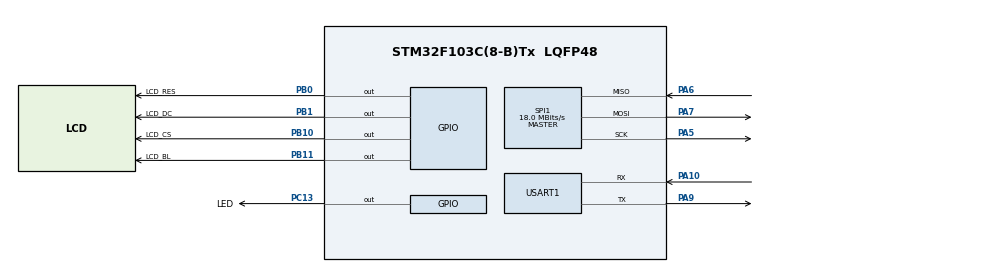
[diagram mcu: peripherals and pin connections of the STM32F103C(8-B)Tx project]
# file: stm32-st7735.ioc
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Mcu.Family=STM32F1
Mcu.Name=STM32F103C(8-B)Tx
Mcu.Package=LQFP48
NVIC.PriorityGroup=NVIC_PRIORITYGROUP_4
PA10.Mode=Asynchronous
PA10.Signal=USART1_RX
PA13.Mode=Serial_Wire
PA13.Signal=SYS_JTMS-SWDIO
PA14.Mode=Serial_Wire
PA14.Signal=SYS_JTCK-SWCLK
PA5.Mode=Full_Duplex_Master
PA5.Signal=SPI1_SCK
PA6.Mode=Full_Duplex_Master
PA6.Signal=SPI1_MISO
PA7.Mode=Full_Duplex_Master
PA7.Signal=SPI1_MOSI
PA9.Mode=Asynchronous
PA9.Signal=USART1_TX
PB0.GPIO_Label=LCD_RES
PB0.Signal=GPIO_Output
PB1.GPIO_Label=LCD_DC
PB1.Signal=GPIO_Output
PB10.GPIO_Label=LCD_CS
PB10.Signal=GPIO_Output
PB11.GPIO_Label=LCD_BL
PB11.Signal=GPIO_Output
PC13-TAMPER-RTC.GPIO_Label=LED
PC13-TAMPER-RTC.Signal=GPIO_Output
PC14-OSC32_IN.Mode=LSE-External-Oscillator
PC14-OSC32_IN.Signal=RCC_OSC32_IN
PC15-OSC32_OUT.Mode=LSE-External-Oscillator
PC15-OSC32_OUT.Signal=RCC_OSC32_OUT
PD0-OSC_IN.Mode=HSE-External-Oscillator
PD0-OSC_IN.Signal=RCC_OSC_IN
PD1-OSC_OUT.Mode=HSE-External-Oscillator
PD1-OSC_OUT.Signal=RCC_OSC_OUT
ProjectManager.HeapSize=0x200
ProjectManager.StackSize=0x400
ProjectManager.TargetToolchain=Makefile
RCC.AHBFreq_Value=72000000
RCC.APB1CLKDivider=RCC_HCLK_DIV2
RCC.APB1Freq_Value=36000000
RCC.APB1TimFreq_Value=72000000
RCC.APB2Freq_Value=72000000
RCC.APB2TimFreq_Value=72000000
RCC.HCLKFreq_Value=72000000
RCC.PLLMUL=RCC_PLL_MUL9
RCC.PLLSourceVirtual=RCC_PLLSOURCE_HSE
RCC.SYSCLKFreq_VALUE=72000000
RCC.SYSCLKSource=RCC_SYSCLKSOURCE_PLLCLK
RCC.USBFreq_Value=72000000
SPI1.BaudRatePrescaler=SPI_BAUDRATEPRESCALER_4
SPI1.CalculateBaudRate=18.0 MBits/s
SPI1.Direction=SPI_DIRECTION_2LINES
SPI1.Mode=SPI_MODE_MASTER
SPI1.VirtualType=VM_MASTER
USART1.VirtualMode=VM_ASYNC
board=custom

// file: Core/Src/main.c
/* USER CODE BEGIN Header */
/**
  ******************************************************************************
  * @file           : main.c
  * @brief          : Main program body
  ******************************************************************************
  * @attention
  *
  * <h2><center>&copy; Copyright (c) 2020 STMicroelectronics.
  * All rights reserved.</center></h2>
  *
  * This software component is licensed by ST under BSD 3-Clause license,
  * the "License"; You may not use this file except in compliance with the
  * License. You may obtain a copy of the License at:
  *                        opensource.org/licenses/BSD-3-Clause
  *
  ******************************************************************************
  */
/* USER CODE END Header */

#include "main.h"
#include "spi.h"
#include "usart.h"
#include "gpio.h"
#include "app.h"

void SystemClock_Config(void);

int main(void)
{

    /* MCU Configuration--------------------------------------------------------*/

    /* Reset of all peripherals, Initializes the Flash interface and the Systick. */
    HAL_Init();

    /* Configure the system clock */
    SystemClock_Config();

    /* Initialize all configured peripherals */
    MX_GPIO_Init();
    MX_SPI1_Init();
    MX_USART1_UART_Init();

    /* Infinite loop */
    /* USER CODE BEGIN WHILE */

    app_start();
    while (1)
    {
        HAL_GPIO_TogglePin(LED_GPIO_Port, LED_Pin);
        HAL_Delay(100);

        /* USER CODE END WHILE */

    }
}

void SystemClock_Config(void)
{
    RCC_OscInitTypeDef RCC_OscInitStruct = {0};
    RCC_ClkInitTypeDef RCC_ClkInitStruct = {0};

    /** Initializes the CPU, AHB and APB busses clocks
     */
    RCC_OscInitStruct.OscillatorType = RCC_OSCILLATORTYPE_HSE;
    RCC_OscInitStruct.HSEState = RCC_HSE_ON;
    RCC_OscInitStruct.HSEPredivValue = RCC_HSE_PREDIV_DIV1;
    RCC_OscInitStruct.HSIState = RCC_HSI_ON;
    RCC_OscInitStruct.PLL.PLLState = RCC_PLL_ON;
    RCC_OscInitStruct.PLL.PLLSource = RCC_PLLSOURCE_HSE;
    RCC_OscInitStruct.PLL.PLLMUL = RCC_PLL_MUL9;
    if (HAL_RCC_OscConfig(&RCC_OscInitStruct) != HAL_OK)
    {
        Error_Handler();
    }
    /** Initializes the CPU, AHB and APB busses clocks
     */
    RCC_ClkInitStruct.ClockType = RCC_CLOCKTYPE_HCLK | RCC_CLOCKTYPE_SYSCLK | RCC_CLOCKTYPE_PCLK1 | RCC_CLOCKTYPE_PCLK2;
    RCC_ClkInitStruct.SYSCLKSource = RCC_SYSCLKSOURCE_PLLCLK;
    RCC_ClkInitStruct.AHBCLKDivider = RCC_SYSCLK_DIV1;
    RCC_ClkInitStruct.APB1CLKDivider = RCC_HCLK_DIV1;
    RCC_ClkInitStruct.APB2CLKDivider = RCC_HCLK_DIV1;

    if (HAL_RCC_ClockConfig(&RCC_ClkInitStruct, FLASH_LATENCY_1) != HAL_OK)
    {
        Error_Handler();
    }
}

void Error_Handler(void)
{
}

/************************ (C) COPYRIGHT STMicroelectronics *****END OF FILE****/
